! (c) 2009  Infineon Technologies AG, Munich
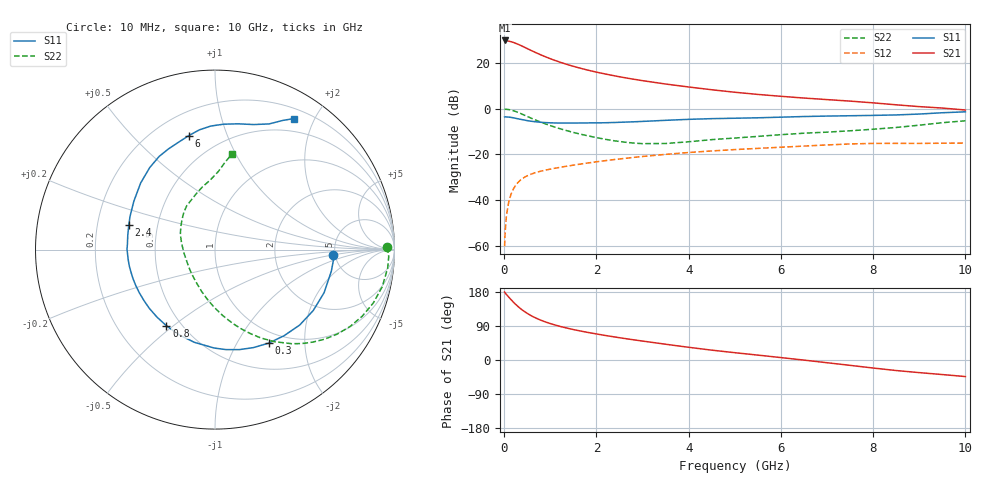
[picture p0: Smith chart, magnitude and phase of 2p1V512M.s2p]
! Infineon Technologies  Discrete & RF Semiconductors
! BFP420
! VCE =  1.5 V,  IC =  12 mA
! Common Emitter S-Parameters:  Nov 2009
# GHz  S  MA  R  50
!  f  S11  S21  S12  S22
! GHz  MAG  ANG  MAG  ANG  MAG  ANG  MAG  ANG
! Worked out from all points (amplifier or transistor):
!   46 points, 10 MHz to 10 GHz, reference 50 ohm
!   highest |S21| = 29.7 dB at 10 MHz (marker M1)
!   |S21| within 3 dB of that: start of sweep to 444.5 MHz
!   unconditionally stable (mu >= 1): 2.155 GHz to end of sweep
!   at 300 MHz: K = 0.22, MSG = 30.2 dB, |S12| = -32.2 dB
!   at 1.7 GHz: K = 0.88, MSG = 20.7 dB, |S12| = -24.0 dB
!   at 10 GHz: K = 1.08, MAG = 5.5 dB, |S12| = -15.0 dB
!   lowest NFmin = 0.95 dB at 900 MHz
!   S11 on the Smith chart (normalised r, x): 10 MHz: 4.80, -0.47; 300 MHz: 0.84, -1.36; 800 MHz: 0.42, -0.47; 2.4 GHz: 0.34, +0.12; 6 GHz: 0.34, +0.74; 10 GHz: 0.32, +1.73
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0.01  0.6581 -2.4  30.72 179.3  0.001 97.8  0.9601 0.8
0.02  0.6632 -4.4  30.05 177.3  0.0019 89.4  0.9687 -2.3
0.05  0.6592 -10.6  30 172.9  0.0047 86.4  0.9675 -6.1
0.1  0.6535 -21.6  29.66 165.9  0.0093 80.7  0.9546 -12.5
0.15  0.6441 -31.8  28.85 159.1  0.0137 76.4  0.931 -18.6
0.2  0.6319 -41.7  27.85 152.8  0.0177 72.2  0.9005 -24.3
0.25  0.615 -51.3  26.59 146.7  0.0213 68.2  0.8657 -29.7
0.3  0.6006 -60.2  25.4 141.2  0.0245 65.0  0.8274 -34.7
0.4  0.5734 -76.4  22.86 131.4  0.03 59.2  0.75 -43.4
0.5  0.5484 -90.5  20.44 123.1  0.0343 55.0  0.6765 -50.8
0.6  0.529 -102.8  18.3 115.9  0.0378 51.7  0.6112 -57.1
0.8  0.5032 -122.6  14.82 104.8  0.0433 47.7  0.5056 -67.4
1  0.491 -138.1  12.3 96.1  0.048 45.5  0.4271 -76.0
1.2  0.4854 -150.3  10.41 89.0  0.0522 44.1  0.3679 -83.6
1.7  0.4867 -173.1  7.408 75.5  0.0628 42.0  0.271 -100.8
2.4  0.4992 164.2  5.18 60.7  0.0778 38.6  0.1982 -126.2
3.5  0.5562 138.1  3.446 41.6  0.1006 31.4  0.1737 -173.3
5.5  0.6317 108.8  2.044 12.9  0.1359 15.7  0.2481 137.9
6  0.6519 102.9  1.858 6.4  0.144 11.8  0.2704 130.0
7  0.6887 92.0  1.575 -7.2  0.1615 3.0  0.3072 115.2
8.5  0.7293 72.8  1.212 -27.8  0.1747 -13.3  0.3886 93.9
10  0.8527 58.9  0.933 -43.7  0.1776 -23.8  0.5433 79.7
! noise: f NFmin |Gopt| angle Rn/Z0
0.9  0.95  0.03  -151  0.13
1.8  1.27  0.13  -152  0.12
2.4  1.38  0.13  -160  0.14
3  1.43  0.22  -145  0.13
4  1.58  0.35  -123  0.17
5  2.03  0.43  -103  0.28
6  2.4  0.47  -91  0.43
